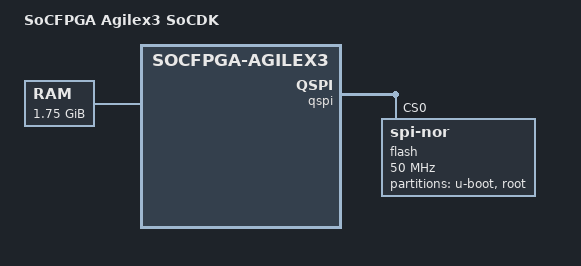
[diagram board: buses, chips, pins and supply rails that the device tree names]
// SPDX-License-Identifier: GPL-2.0-only
/*
 * Copyright (C) 2025, Altera Corporation
 */
#include "socfpga_agilex3_socdk.dts"

/ {
	model = "SoCFPGA Agilex3 SoCDK";
	compatible = "intel,socfpga-agilex3-socdk", "intel,socfpga-agilex3";

	chosen {
		stdout-path = "serial0:115200n8";
		bootargs = "console=ttys0,115200 earlycon panic=-1 root=/dev/mtdblock1 \
			rw rootfstype=jffs2 rootwait";
	};

	memory {
		device_type = "memory";
		reg = <0 0x80000000 0 0x70000000>;
	};
};

&qspi {
	status = "okay";
	cdns,fifo-depth = <0x400>;
	/delete-node/ flash@0;

	flash@0 {
		#address-cells = <1>;
		#size-cells = <1>;
		compatible = "jedec,spi-nor";
		reg = <0>;
		spi-max-frequency = <50000000>;
		m25p,fast-read;
		cdns,read-delay = <2>;
		cdns,tshsl-ns = <50>;
		cdns,tsd2d-ns = <50>;
		cdns,tchsh-ns = <4>;
		cdns,tslch-ns = <4>;
		spi-tx-bus-width=<4>;
		spi-rx-bus-width=<4>;

		partitions {
			compatible = "fixed-partitions";
			#address-cells = <1>;
			#size-cells = <1>;
			rsu-handle = <&qspi_boot>;

			qspi_boot: partition@0 {
				label = "u-boot";
				reg = <0x0 0x0340000>;
			};

			root: partition@3400000  {
				label = "root";
				reg = <0x03400000 0x04FFFFFF>;
			};
		};
	};
};
